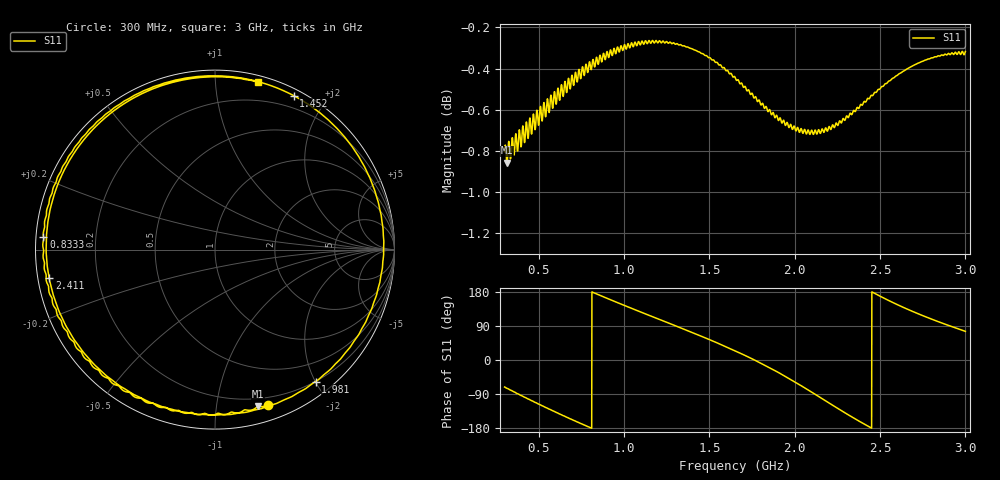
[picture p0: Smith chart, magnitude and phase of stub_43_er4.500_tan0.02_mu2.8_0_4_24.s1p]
! Chirptenna · simulación 3D de un stub abierto
# HZ S RI R 50
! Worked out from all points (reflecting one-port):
!   2001 points, 300 MHz to 3 GHz, reference 50 ohm
!   lowest |S11| = -0.9 dB at 313.5 MHz (marker M1), VSWR 20.27, Z = 6.68 - j65.1 ohm
!   phase of S11 starts at -71 deg and turns -573 deg over the sweep
!   S11 on the Smith chart (normalised r, x): 300 MHz: 0.14, -1.39; 833.2 MHz: 0.02, +0.04; 1.452 GHz: 0.07, +1.63; 1.981 GHz: 0.20, -2.01; 2.411 GHz: 0.03, -0.09; 3 GHz: 0.05, +1.29
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3e8  0.2936 -0.863
3.135e8  0.2394 -0.8738
3.7695e8  0.0153 -0.9121
4.5795e8  -0.2734 -0.8791
5.3895e8  -0.5331 -0.7619
6.375e8  -0.7806 -0.5308
7.2795e8  -0.9111 -0.2649
8.3325e8  -0.9557 0.0728
9.75e8  -0.8267 0.4971
1.15455e9  -0.4312 0.8675
1.3125e9  0.0294 0.9679
1.45155e9  0.4382 0.8577
1.5501e9  0.6862 0.6681
1.65e9  0.8661 0.3914
1.7391e9  0.9372 0.0896
1.82145e9  0.9098 -0.2117
1.9011e9  0.7848 -0.4958
1.98075e9  0.5608 -0.7349
1.9875e9  0.5381 -0.75
2.06985e9  0.2135 -0.8957
2.15085e9  -0.1478 -0.909
2.23185e9  -0.4901 -0.7832
2.325e9  -0.7868 -0.4985
2.4114e9  -0.9237 -0.1599
2.5248e9  -0.9037 0.2808
2.6625e9  -0.659 0.6912
2.8245e9  -0.2318 0.9329
3e9  0.2402 0.9337
